VERSION 5.7 ;
BUSBITCHARS "[]" ;
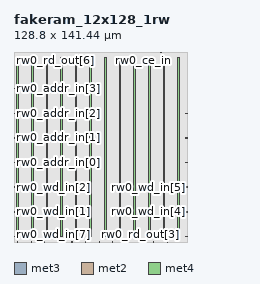
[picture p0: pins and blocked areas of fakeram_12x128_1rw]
MACRO fakeram_12x128_1rw
  FOREIGN fakeram_12x128_1rw 0 0 ;
  SYMMETRY X Y R90 ;
  SIZE 128.800 BY 141.440 ;
  CLASS BLOCK ;
  PIN rw0_wd_in[0]
    DIRECTION INPUT ;
    USE SIGNAL ;
    SHAPE ABUTMENT ;
    PORT
      LAYER met3 ;
      RECT 0.000 3.930 0.900 4.230 ;
    END
  END rw0_wd_in[0]
  PIN rw0_wd_in[1]
    DIRECTION INPUT ;
    USE SIGNAL ;
    SHAPE ABUTMENT ;
    PORT
      LAYER met3 ;
      RECT 0.000 22.290 0.900 22.590 ;
    END
  END rw0_wd_in[1]
  PIN rw0_wd_in[2]
    DIRECTION INPUT ;
    USE SIGNAL ;
    SHAPE ABUTMENT ;
    PORT
      LAYER met3 ;
      RECT 0.000 40.650 0.900 40.950 ;
    END
  END rw0_wd_in[2]
  PIN rw0_wd_in[3]
    DIRECTION INPUT ;
    USE SIGNAL ;
    SHAPE ABUTMENT ;
    PORT
      LAYER met3 ;
      RECT 127.900 3.930 128.800 4.230 ;
    END
  END rw0_wd_in[3]
  PIN rw0_wd_in[4]
    DIRECTION INPUT ;
    USE SIGNAL ;
    SHAPE ABUTMENT ;
    PORT
      LAYER met3 ;
      RECT 127.900 22.290 128.800 22.590 ;
    END
  END rw0_wd_in[4]
  PIN rw0_wd_in[5]
    DIRECTION INPUT ;
    USE SIGNAL ;
    SHAPE ABUTMENT ;
    PORT
      LAYER met3 ;
      RECT 127.900 40.650 128.800 40.950 ;
    END
  END rw0_wd_in[5]
  PIN rw0_wd_in[6]
    DIRECTION INPUT ;
    USE SIGNAL ;
    SHAPE ABUTMENT ;
    PORT
      LAYER met2 ;
      RECT 2.690 0.000 2.830 0.420 ;
    END
  END rw0_wd_in[6]
  PIN rw0_wd_in[7]
    DIRECTION INPUT ;
    USE SIGNAL ;
    SHAPE ABUTMENT ;
    PORT
      LAYER met2 ;
      RECT 12.810 0.000 12.950 0.420 ;
    END
  END rw0_wd_in[7]
  PIN rw0_wd_in[8]
    DIRECTION INPUT ;
    USE SIGNAL ;
    SHAPE ABUTMENT ;
    PORT
      LAYER met2 ;
      RECT 22.930 0.000 23.070 0.420 ;
    END
  END rw0_wd_in[8]
  PIN rw0_wd_in[9]
    DIRECTION INPUT ;
    USE SIGNAL ;
    SHAPE ABUTMENT ;
    PORT
      LAYER met2 ;
      RECT 33.050 0.000 33.190 0.420 ;
    END
  END rw0_wd_in[9]
  PIN rw0_wd_in[10]
    DIRECTION INPUT ;
    USE SIGNAL ;
    SHAPE ABUTMENT ;
    PORT
      LAYER met2 ;
      RECT 43.170 0.000 43.310 0.420 ;
    END
  END rw0_wd_in[10]
  PIN rw0_wd_in[11]
    DIRECTION INPUT ;
    USE SIGNAL ;
    SHAPE ABUTMENT ;
    PORT
      LAYER met2 ;
      RECT 53.290 0.000 53.430 0.420 ;
    END
  END rw0_wd_in[11]
  PIN rw0_rd_out[0]
    DIRECTION OUTPUT ;
    USE SIGNAL ;
    SHAPE ABUTMENT ;
    PORT
      LAYER met2 ;
      RECT 63.410 0.000 63.550 0.420 ;
    END
  END rw0_rd_out[0]
  PIN rw0_rd_out[1]
    DIRECTION OUTPUT ;
    USE SIGNAL ;
    SHAPE ABUTMENT ;
    PORT
      LAYER met2 ;
      RECT 73.530 0.000 73.670 0.420 ;
    END
  END rw0_rd_out[1]
  PIN rw0_rd_out[2]
    DIRECTION OUTPUT ;
    USE SIGNAL ;
    SHAPE ABUTMENT ;
    PORT
      LAYER met2 ;
      RECT 83.650 0.000 83.790 0.420 ;
    END
  END rw0_rd_out[2]
  PIN rw0_rd_out[3]
    DIRECTION OUTPUT ;
    USE SIGNAL ;
    SHAPE ABUTMENT ;
    PORT
      LAYER met2 ;
      RECT 93.770 0.000 93.910 0.420 ;
    END
  END rw0_rd_out[3]
  PIN rw0_rd_out[4]
    DIRECTION OUTPUT ;
    USE SIGNAL ;
    SHAPE ABUTMENT ;
    PORT
      LAYER met2 ;
      RECT 103.890 0.000 104.030 0.420 ;
    END
  END rw0_rd_out[4]
  PIN rw0_rd_out[5]
    DIRECTION OUTPUT ;
    USE SIGNAL ;
    SHAPE ABUTMENT ;
    PORT
      LAYER met2 ;
      RECT 114.010 0.000 114.150 0.420 ;
    END
  END rw0_rd_out[5]
  PIN rw0_rd_out[6]
    DIRECTION OUTPUT ;
    USE SIGNAL ;
    SHAPE ABUTMENT ;
    PORT
      LAYER met2 ;
      RECT 2.690 141.020 2.830 141.440 ;
    END
  END rw0_rd_out[6]
  PIN rw0_rd_out[7]
    DIRECTION OUTPUT ;
    USE SIGNAL ;
    SHAPE ABUTMENT ;
    PORT
      LAYER met2 ;
      RECT 16.030 141.020 16.170 141.440 ;
    END
  END rw0_rd_out[7]
  PIN rw0_rd_out[8]
    DIRECTION OUTPUT ;
    USE SIGNAL ;
    SHAPE ABUTMENT ;
    PORT
      LAYER met2 ;
      RECT 29.370 141.020 29.510 141.440 ;
    END
  END rw0_rd_out[8]
  PIN rw0_rd_out[9]
    DIRECTION OUTPUT ;
    USE SIGNAL ;
    SHAPE ABUTMENT ;
    PORT
      LAYER met2 ;
      RECT 42.710 141.020 42.850 141.440 ;
    END
  END rw0_rd_out[9]
  PIN rw0_rd_out[10]
    DIRECTION OUTPUT ;
    USE SIGNAL ;
    SHAPE ABUTMENT ;
    PORT
      LAYER met2 ;
      RECT 56.050 141.020 56.190 141.440 ;
    END
  END rw0_rd_out[10]
  PIN rw0_rd_out[11]
    DIRECTION OUTPUT ;
    USE SIGNAL ;
    SHAPE ABUTMENT ;
    PORT
      LAYER met2 ;
      RECT 69.390 141.020 69.530 141.440 ;
    END
  END rw0_rd_out[11]
  PIN rw0_addr_in[0]
    DIRECTION INPUT ;
    USE SIGNAL ;
    SHAPE ABUTMENT ;
    PORT
      LAYER met3 ;
      RECT 0.000 59.010 0.900 59.310 ;
    END
  END rw0_addr_in[0]
  PIN rw0_addr_in[1]
    DIRECTION INPUT ;
    USE SIGNAL ;
    SHAPE ABUTMENT ;
    PORT
      LAYER met3 ;
      RECT 0.000 77.370 0.900 77.670 ;
    END
  END rw0_addr_in[1]
  PIN rw0_addr_in[2]
    DIRECTION INPUT ;
    USE SIGNAL ;
    SHAPE ABUTMENT ;
    PORT
      LAYER met3 ;
      RECT 0.000 95.730 0.900 96.030 ;
    END
  END rw0_addr_in[2]
  PIN rw0_addr_in[3]
    DIRECTION INPUT ;
    USE SIGNAL ;
    SHAPE ABUTMENT ;
    PORT
      LAYER met3 ;
      RECT 0.000 114.090 0.900 114.390 ;
    END
  END rw0_addr_in[3]
  PIN rw0_addr_in[4]
    DIRECTION INPUT ;
    USE SIGNAL ;
    SHAPE ABUTMENT ;
    PORT
      LAYER met3 ;
      RECT 127.900 59.010 128.800 59.310 ;
    END
  END rw0_addr_in[4]
  PIN rw0_addr_in[5]
    DIRECTION INPUT ;
    USE SIGNAL ;
    SHAPE ABUTMENT ;
    PORT
      LAYER met3 ;
      RECT 127.900 77.370 128.800 77.670 ;
    END
  END rw0_addr_in[5]
  PIN rw0_addr_in[6]
    DIRECTION INPUT ;
    USE SIGNAL ;
    SHAPE ABUTMENT ;
    PORT
      LAYER met3 ;
      RECT 127.900 95.730 128.800 96.030 ;
    END
  END rw0_addr_in[6]
  PIN rw0_we_in
    DIRECTION INPUT ;
    USE SIGNAL ;
    SHAPE ABUTMENT ;
    PORT
      LAYER met2 ;
      RECT 82.730 141.020 82.870 141.440 ;
    END
  END rw0_we_in
  PIN rw0_ce_in
    DIRECTION INPUT ;
    USE SIGNAL ;
    SHAPE ABUTMENT ;
    PORT
      LAYER met2 ;
      RECT 96.070 141.020 96.210 141.440 ;
    END
  END rw0_ce_in
  PIN rw0_clk
    DIRECTION INPUT ;
    USE SIGNAL ;
    SHAPE ABUTMENT ;
    PORT
      LAYER met2 ;
      RECT 109.410 141.020 109.550 141.440 ;
    END
  END rw0_clk
  PIN VSS
    DIRECTION INOUT ;
    USE GROUND ;
    PORT
      LAYER met4 ;
      RECT 2.160 4.080 3.360 137.360 ;
      RECT 13.040 4.080 14.240 137.360 ;
      RECT 23.920 4.080 25.120 137.360 ;
      RECT 34.800 4.080 36.000 137.360 ;
      RECT 45.680 4.080 46.880 137.360 ;
      RECT 56.560 4.080 57.760 137.360 ;
      RECT 67.440 4.080 68.640 137.360 ;
      RECT 78.320 4.080 79.520 137.360 ;
      RECT 89.200 4.080 90.400 137.360 ;
      RECT 100.080 4.080 101.280 137.360 ;
      RECT 110.960 4.080 112.160 137.360 ;
      RECT 121.840 4.080 123.040 137.360 ;
    END
  END VSS
  PIN VDD
    DIRECTION INOUT ;
    USE POWER ;
    PORT
      LAYER met4 ;
      RECT 2.160 4.080 3.360 137.360 ;
      RECT 13.040 4.080 14.240 137.360 ;
      RECT 23.920 4.080 25.120 137.360 ;
      RECT 34.800 4.080 36.000 137.360 ;
      RECT 45.680 4.080 46.880 137.360 ;
      RECT 56.560 4.080 57.760 137.360 ;
      RECT 67.440 4.080 68.640 137.360 ;
      RECT 78.320 4.080 79.520 137.360 ;
      RECT 89.200 4.080 90.400 137.360 ;
      RECT 100.080 4.080 101.280 137.360 ;
      RECT 110.960 4.080 112.160 137.360 ;
      RECT 121.840 4.080 123.040 137.360 ;
    END
  END VDD
  OBS
    LAYER met1 ;
    RECT 0 0 128.800 141.440 ;
    LAYER met2 ;
    RECT 0 0 128.800 141.440 ;
    LAYER met3 ;
    RECT 0 0 128.800 141.440 ;
    LAYER met4 ;
    RECT 0 0 128.800 141.440 ;
  END
END fakeram_12x128_1rw

END LIBRARY
